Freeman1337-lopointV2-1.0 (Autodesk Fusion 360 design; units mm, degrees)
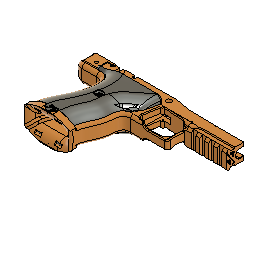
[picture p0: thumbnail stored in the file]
named bodies: "Freeman1337-lopoint-grip-R", "Freeman1337-lopoint-grip-L"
